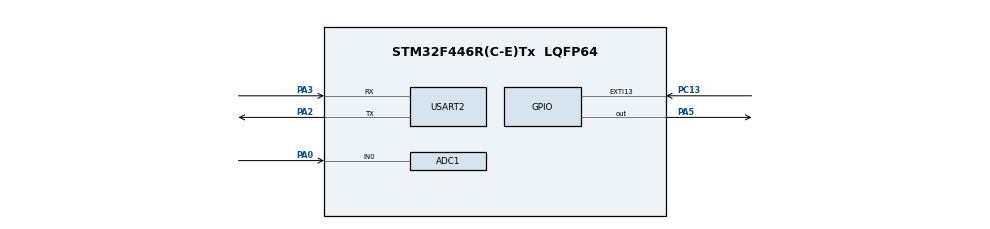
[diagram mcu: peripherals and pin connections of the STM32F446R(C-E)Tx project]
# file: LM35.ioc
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ADC1.Channel-0\#ChannelRegularConversion=ADC_CHANNEL_0
ADC1.Channel-1\#ChannelRegularConversion=ADC_CHANNEL_0
ADC1.Channel-10\#ChannelRegularConversion=ADC_CHANNEL_0
ADC1.Channel-11\#ChannelRegularConversion=ADC_CHANNEL_0
ADC1.Channel-12\#ChannelRegularConversion=ADC_CHANNEL_0
ADC1.Channel-13\#ChannelRegularConversion=ADC_CHANNEL_0
ADC1.Channel-14\#ChannelRegularConversion=ADC_CHANNEL_0
ADC1.Channel-15\#ChannelRegularConversion=ADC_CHANNEL_0
ADC1.Channel-2\#ChannelRegularConversion=ADC_CHANNEL_0
ADC1.Channel-3\#ChannelRegularConversion=ADC_CHANNEL_0
ADC1.Channel-4\#ChannelRegularConversion=ADC_CHANNEL_0
ADC1.Channel-5\#ChannelRegularConversion=ADC_CHANNEL_0
ADC1.Channel-6\#ChannelRegularConversion=ADC_CHANNEL_0
ADC1.Channel-7\#ChannelRegularConversion=ADC_CHANNEL_0
ADC1.Channel-8\#ChannelRegularConversion=ADC_CHANNEL_0
ADC1.Channel-9\#ChannelRegularConversion=ADC_CHANNEL_0
ADC1.ContinuousConvMode=ENABLE
ADC1.NbrOfConversion=16
ADC1.NbrOfConversionFlag=1
ADC1.Rank-0\#ChannelRegularConversion=1
ADC1.Rank-1\#ChannelRegularConversion=2
ADC1.Rank-10\#ChannelRegularConversion=11
ADC1.Rank-11\#ChannelRegularConversion=12
ADC1.Rank-12\#ChannelRegularConversion=13
ADC1.Rank-13\#ChannelRegularConversion=14
ADC1.Rank-14\#ChannelRegularConversion=15
ADC1.Rank-15\#ChannelRegularConversion=16
ADC1.Rank-2\#ChannelRegularConversion=3
ADC1.Rank-3\#ChannelRegularConversion=4
ADC1.Rank-4\#ChannelRegularConversion=5
ADC1.Rank-5\#ChannelRegularConversion=6
ADC1.Rank-6\#ChannelRegularConversion=7
ADC1.Rank-7\#ChannelRegularConversion=8
ADC1.Rank-8\#ChannelRegularConversion=9
ADC1.Rank-9\#ChannelRegularConversion=10
ADC1.SamplingTime-0\#ChannelRegularConversion=ADC_SAMPLETIME_3CYCLES
ADC1.SamplingTime-1\#ChannelRegularConversion=ADC_SAMPLETIME_3CYCLES
ADC1.SamplingTime-10\#ChannelRegularConversion=ADC_SAMPLETIME_3CYCLES
ADC1.SamplingTime-11\#ChannelRegularConversion=ADC_SAMPLETIME_3CYCLES
ADC1.SamplingTime-12\#ChannelRegularConversion=ADC_SAMPLETIME_3CYCLES
ADC1.SamplingTime-13\#ChannelRegularConversion=ADC_SAMPLETIME_3CYCLES
ADC1.SamplingTime-14\#ChannelRegularConversion=ADC_SAMPLETIME_3CYCLES
ADC1.SamplingTime-15\#ChannelRegularConversion=ADC_SAMPLETIME_3CYCLES
ADC1.SamplingTime-2\#ChannelRegularConversion=ADC_SAMPLETIME_3CYCLES
ADC1.SamplingTime-3\#ChannelRegularConversion=ADC_SAMPLETIME_3CYCLES
ADC1.SamplingTime-4\#ChannelRegularConversion=ADC_SAMPLETIME_3CYCLES
ADC1.SamplingTime-5\#ChannelRegularConversion=ADC_SAMPLETIME_3CYCLES
ADC1.SamplingTime-6\#ChannelRegularConversion=ADC_SAMPLETIME_3CYCLES
ADC1.SamplingTime-7\#ChannelRegularConversion=ADC_SAMPLETIME_3CYCLES
ADC1.SamplingTime-8\#ChannelRegularConversion=ADC_SAMPLETIME_3CYCLES
ADC1.SamplingTime-9\#ChannelRegularConversion=ADC_SAMPLETIME_3CYCLES
ADC1.ScanConvMode=ENABLE
ADC1.master=1
Dma.ADC1.0.Direction=DMA_PERIPH_TO_MEMORY
Dma.ADC1.0.FIFOMode=DMA_FIFOMODE_DISABLE
Dma.ADC1.0.Instance=DMA2_Stream0
Dma.ADC1.0.MemDataAlignment=DMA_MDATAALIGN_WORD
Dma.ADC1.0.MemInc=DMA_MINC_ENABLE
Dma.ADC1.0.Mode=DMA_CIRCULAR
Dma.ADC1.0.PeriphDataAlignment=DMA_PDATAALIGN_WORD
Dma.ADC1.0.PeriphInc=DMA_PINC_DISABLE
Dma.ADC1.0.Priority=DMA_PRIORITY_LOW
Dma.Request0=ADC1
Mcu.Family=STM32F4
Mcu.Name=STM32F446R(C-E)Tx
Mcu.Package=LQFP64
NVIC.DMA2_Stream0_IRQn=true\:0\:0\:false\:false\:true\:false\:true
NVIC.PriorityGroup=NVIC_PRIORITYGROUP_0
NVIC.RCC_IRQn=true\:0\:0\:false\:false\:true\:true\:false
PA0-WKUP.Signal=ADCx_IN0
PA13.Signal=SYS_JTMS-SWDIO
PA14.Signal=SYS_JTCK-SWCLK
PA2.GPIO_Mode=GPIO_MODE_AF_PP
PA2.GPIO_PuPd=GPIO_PULLUP
PA2.GPIO_Speed=GPIO_SPEED_FREQ_VERY_HIGH
PA2.Mode=Asynchronous
PA2.Signal=USART2_TX
PA3.GPIO_Mode=GPIO_MODE_AF_PP
PA3.GPIO_PuPd=GPIO_PULLUP
PA3.GPIO_Speed=GPIO_SPEED_FREQ_VERY_HIGH
PA3.Mode=Asynchronous
PA3.Signal=USART2_RX
PA5.GPIO_ModeDefaultOutputPP=GPIO_MODE_OUTPUT_PP
PA5.GPIO_PuPd=GPIO_NOPULL
PA5.GPIO_Speed=GPIO_SPEED_FREQ_LOW
PA5.PinState=GPIO_PIN_RESET
PA5.Signal=GPIO_Output
PB3.Signal=SYS_JTDO-SWO
PC13.GPIO_ModeDefaultEXTI=GPIO_MODE_IT_RISING
PC13.GPIO_PuPd=GPIO_NOPULL
PC13.Signal=GPXTI13
PC14-OSC32_IN.Signal=RCC_OSC32_IN
PC15-OSC32_OUT.Signal=RCC_OSC32_OUT
<<<<<<< HEAD
<<<<<<< HEAD
PH0-OSC_IN.Mode=HSE-External-Oscillator
PH0-OSC_IN.Signal=RCC_OSC_IN
PH1-OSC_OUT.Mode=HSE-External-Oscillator
=======
PH0-OSC_IN.Signal=RCC_OSC_IN
>>>>>>> parent of ff74db9... add RCC
=======
PH0-OSC_IN.Signal=RCC_OSC_IN
>>>>>>> parent of ff74db9... add RCC
PH1-OSC_OUT.Signal=RCC_OSC_OUT
ProjectManager.HeapSize=0x400
ProjectManager.StackSize=0x400
ProjectManager.TargetToolchain=TrueSTUDIO
<<<<<<< HEAD
RCC.APB1TimFreq_Value=36000000
RCC.PLLSourceVirtual=RCC_PLLSOURCE_HSE
RCC.SYSCLKSource=RCC_SYSCLKSOURCE_PLLCLK
=======
RCC.AHBFreq_Value=72000000
RCC.APB1CLKDivider=RCC_HCLK_DIV2
RCC.APB1Freq_Value=36000000
RCC.APB1TimFreq_Value=72000000
RCC.APB2Freq_Value=72000000
RCC.APB2TimFreq_Value=72000000
RCC.CortexFreq_Value=72000000
RCC.FLatency-AdvancedSettings=FLASH_LATENCY_2
RCC.HCLKFreq_Value=72000000
RCC.HSE_VALUE=8000000
RCC.HSI_VALUE=16000000
RCC.LSE_VALUE=32768
RCC.PLLM=8
RCC.PLLN=72
RCC.SYSCLKFreq_VALUE=72000000
RCC.SYSCLKSource=RCC_SYSCLKSOURCE_PLLCLK
RCC.USBFreq_Value=72000000
RCC.VCOOutputFreq_Value=144000000
>>>>>>> parent of ff74db9... add RCC
SH.ADCx_IN0.0=ADC1_IN0,IN0
USART2.VirtualMode=VM_ASYNC
board=NUCLEO-F446RE

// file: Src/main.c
/* USER CODE BEGIN Header */
/**
  ******************************************************************************
  * @file           : main.c
  * @brief          : Main program body
  ******************************************************************************
  * @attention
  *
  * <h2><center>&copy; Copyright (c) 2019 STMicroelectronics.
  * All rights reserved.</center></h2>
  *
  * This software component is licensed by ST under BSD 3-Clause license,
  * the "License"; You may not use this file except in compliance with the
  * License. You may obtain a copy of the License at:
  *                        opensource.org/licenses/BSD-3-Clause
  *
  ******************************************************************************
  */
/* USER CODE END Header */

#include "main.h"

ADC_HandleTypeDef hadc1;
DMA_HandleTypeDef hdma_adc1;

UART_HandleTypeDef huart2;

void SystemClock_Config(void);
static void MX_GPIO_Init(void);
static void MX_DMA_Init(void);
static void MX_ADC1_Init(void);
static void MX_USART2_UART_Init(void);
/* USER CODE BEGIN PFP */
void SET_ADCOption1 (FunctionalState NewState);
void SET_ADCOption2 (uint32_t ADCxDC2, FunctionalState NewState);
/* USER CODE END PFP */

/* USER CODE BEGIN 0 */
uint32_t adc_val, buffer;
void HAL_ADC_ConvCpltCallback(ADC_HandleTypeDef* hadc)
{

/* for INTERRUPT uncomment the line below */
//	buffer = HAL_ADC_GetValue(&hadc1);

/*If continuousconversion mode is DISABLED uncomment below*/
//HAL_ADC_Start_IT (&hadc1);

/* for DMA uncomment the line below */
	adc_val = buffer;
}

int __io_putchar(int ch)
 {
  uint8_t c[1];
  c[0] = ch & 0x00FF;
  HAL_UART_Transmit(&huart2, &*c, 1, 10);
  return ch;
 }

 int _write(int file,char *ptr, int len)
 {
  int DataIdx;
  for(DataIdx= 0; DataIdx< len; DataIdx++)
  {
  __io_putchar(*ptr++);
  }
 return len;
 }
/* USER CODE END 0 */

int main(void)
{

  /* MCU Configuration--------------------------------------------------------*/

  /* Reset of all peripherals, Initializes the Flash interface and the Systick. */
  HAL_Init();

  /* Configure the system clock */
  SystemClock_Config();

  /* Initialize all configured peripherals */
  MX_GPIO_Init();
  MX_DMA_Init();
  MX_ADC1_Init();
  MX_USART2_UART_Init();
  /* USER CODE BEGIN 2 */
  //SET_ADCOption1 (ENABLE);
 //SET_ADCOption2 (SYSCFG_PMC_ADCxDC2, ENABLE);
  /* USER CODE END 2 */

  /* Infinite loop */
  while (1)
  {

    /* USER CODE BEGIN 3 */
		HAL_ADC_Start (&hadc1);
	  HAL_ADC_PollForConversion(&hadc1, 10);  // poll for conversion
	  adc_val = HAL_ADC_GetValue(&hadc1);  // get the adc value
		printf("ADC_Value == %d \n\r", adc_val);
	//	HAL_ADC_Stop(&hadc1);  // stop adc
		HAL_Delay (50);  // wait for 500ms
  }
  /* USER CODE END 3 */
}

<<<<<<< HEAD
<<<<<<< HEAD
<<<<<<< HEAD
=======
=======
>>>>>>> parent of ff74db9... add RCC
=======
>>>>>>> parent of ff74db9... add RCC
/**
* @brief Enables or disables the ADC Option_1 configuration.
 * @param NewState: new state of the ADCDC1 bit.
 * This parameter can be: ENABLE or DISABLE.
 * @retval None
 */
void SET_ADCOption1 (FunctionalState NewState)
{

 /* ENABLE PWR clock */
	__HAL_RCC_PWR_CLK_ENABLE();

 if (NewState != DISABLE)
 {
 /* Set ADCDC1 bit */
 PWR->CR |= ((uint32_t)PWR_CR_ADCDC1);
 }
 else
 {
 /* Reset ADCDC1 bit */
 PWR->CR &= (uint32_t)(~PWR_CR_ADCDC1);
 }
}

/**
 * @brief Enables or disables the ADCx Option_2 configuration.
 * @param ADCxDC2: The ADCxDC2 bit to be used.
 * This parameter can be one of the following values:
 * @arg SYSCFG_PMC_ADCxDC2: All ADCxDC2 bits
 * @arg SYSCFG_PMC_ADC1DC2: ADC1DC2 bit
 * @arg SYSCFG_PMC_ADC2DC2: ADC2DC2 bit
 * @arg SYSCFG_PMC_ADC3DC2: ADC3DC2 bit
 * @param NewState: new state of the ADCxDC2 bit.
 * This parameter can be: ENABLE or DISABLE.
 * @retval None
 */
void SET_ADCOption2 (uint32_t ADCxDC2, FunctionalState NewState)
{

 /* Enable the SYSCFG clock*/
	__HAL_RCC_SYSCFG_CLK_ENABLE();

 if (NewState != DISABLE)
 {
 /* Set the ADCxDC2 */
 SYSCFG->PMC |= (uint32_t)ADCxDC2;
 }
 else
 {
 /* Reset the ADCxDC2 */
 SYSCFG->PMC &=(uint32_t)(~ADCxDC2);
}
}
>>>>>>> parent of ff74db9... add RCC

void SystemClock_Config(void)
{
  RCC_OscInitTypeDef RCC_OscInitStruct = {0};
  RCC_ClkInitTypeDef RCC_ClkInitStruct = {0};

  /** Configure the main internal regulator output voltage
  */
  __HAL_RCC_PWR_CLK_ENABLE();
  __HAL_PWR_VOLTAGESCALING_CONFIG(PWR_REGULATOR_VOLTAGE_SCALE3);
  /** Initializes the CPU, AHB and APB busses clocks
  */
<<<<<<< HEAD
<<<<<<< HEAD
<<<<<<< HEAD
  RCC_OscInitStruct.OscillatorType = RCC_OSCILLATORTYPE_HSE;
  RCC_OscInitStruct.HSEState = RCC_HSE_ON;
  RCC_OscInitStruct.PLL.PLLState = RCC_PLL_ON;
  RCC_OscInitStruct.PLL.PLLSource = RCC_PLLSOURCE_HSE;
  RCC_OscInitStruct.PLL.PLLM = 16;
  RCC_OscInitStruct.PLL.PLLN = 192;
=======
  RCC_OscInitStruct.OscillatorType = RCC_OSCILLATORTYPE_HSI;
  RCC_OscInitStruct.HSIState = RCC_HSI_ON;
  RCC_OscInitStruct.HSICalibrationValue = RCC_HSICALIBRATION_DEFAULT;
  RCC_OscInitStruct.PLL.PLLState = RCC_PLL_ON;
=======
  RCC_OscInitStruct.OscillatorType = RCC_OSCILLATORTYPE_HSI;
  RCC_OscInitStruct.HSIState = RCC_HSI_ON;
  RCC_OscInitStruct.HSICalibrationValue = RCC_HSICALIBRATION_DEFAULT;
  RCC_OscInitStruct.PLL.PLLState = RCC_PLL_ON;
>>>>>>> parent of ff74db9... add RCC
=======
  RCC_OscInitStruct.OscillatorType = RCC_OSCILLATORTYPE_HSI;
  RCC_OscInitStruct.HSIState = RCC_HSI_ON;
  RCC_OscInitStruct.HSICalibrationValue = RCC_HSICALIBRATION_DEFAULT;
  RCC_OscInitStruct.PLL.PLLState = RCC_PLL_ON;
>>>>>>> parent of ff74db9... add RCC
  RCC_OscInitStruct.PLL.PLLSource = RCC_PLLSOURCE_HSI;
  RCC_OscInitStruct.PLL.PLLM = 8;
  RCC_OscInitStruct.PLL.PLLN = 72;
>>>>>>> parent of ff74db9... add RCC
  RCC_OscInitStruct.PLL.PLLP = RCC_PLLP_DIV2;
  RCC_OscInitStruct.PLL.PLLQ = 2;
  RCC_OscInitStruct.PLL.PLLR = 2;
  if (HAL_RCC_OscConfig(&RCC_OscInitStruct) != HAL_OK)
  {
    Error_Handler();
  }
  /** Initializes the CPU, AHB and APB busses clocks
  */
  RCC_ClkInitStruct.ClockType = RCC_CLOCKTYPE_HCLK|RCC_CLOCKTYPE_SYSCLK
                              |RCC_CLOCKTYPE_PCLK1|RCC_CLOCKTYPE_PCLK2;
  RCC_ClkInitStruct.SYSCLKSource = RCC_SYSCLKSOURCE_PLLCLK;
  RCC_ClkInitStruct.AHBCLKDivider = RCC_SYSCLK_DIV1;
  RCC_ClkInitStruct.APB1CLKDivider = RCC_HCLK_DIV1;
  RCC_ClkInitStruct.APB2CLKDivider = RCC_HCLK_DIV1;

  if (HAL_RCC_ClockConfig(&RCC_ClkInitStruct, FLASH_LATENCY_0) != HAL_OK)
  {
    Error_Handler();
  }
}

static void MX_ADC1_Init(void)
{

  ADC_ChannelConfTypeDef sConfig = {0};

  /** Configure the global features of the ADC (Clock, Resolution, Data Alignment and number of conversion)
  */
  hadc1.Instance = ADC1;
  hadc1.Init.ClockPrescaler = ADC_CLOCK_SYNC_PCLK_DIV2;
  hadc1.Init.Resolution = ADC_RESOLUTION_12B;
  hadc1.Init.ScanConvMode = ENABLE;
  hadc1.Init.ContinuousConvMode = ENABLE;
  hadc1.Init.DiscontinuousConvMode = DISABLE;
  hadc1.Init.ExternalTrigConvEdge = ADC_EXTERNALTRIGCONVEDGE_NONE;
  hadc1.Init.ExternalTrigConv = ADC_SOFTWARE_START;
  hadc1.Init.DataAlign = ADC_DATAALIGN_RIGHT;
  hadc1.Init.NbrOfConversion = 16;
  hadc1.Init.DMAContinuousRequests = DISABLE;
  hadc1.Init.EOCSelection = ADC_EOC_SINGLE_CONV;
  if (HAL_ADC_Init(&hadc1) != HAL_OK)
  {
    Error_Handler();
  }
  /** Configure for the selected ADC regular channel its corresponding rank in the sequencer and its sample time.
  */
  sConfig.Channel = ADC_CHANNEL_0;
  sConfig.Rank = 1;
  sConfig.SamplingTime = ADC_SAMPLETIME_3CYCLES;
  if (HAL_ADC_ConfigChannel(&hadc1, &sConfig) != HAL_OK)
  {
    Error_Handler();
  }
  /** Configure for the selected ADC regular channel its corresponding rank in the sequencer and its sample time.
  */
  sConfig.Rank = 2;
  if (HAL_ADC_ConfigChannel(&hadc1, &sConfig) != HAL_OK)
  {
    Error_Handler();
  }
  /** Configure for the selected ADC regular channel its corresponding rank in the sequencer and its sample time.
  */
  sConfig.Rank = 3;
  if (HAL_ADC_ConfigChannel(&hadc1, &sConfig) != HAL_OK)
  {
    Error_Handler();
  }
  /** Configure for the selected ADC regular channel its corresponding rank in the sequencer and its sample time.
  */
  sConfig.Rank = 4;
  if (HAL_ADC_ConfigChannel(&hadc1, &sConfig) != HAL_OK)
  {
    Error_Handler();
  }
  /** Configure for the selected ADC regular channel its corresponding rank in the sequencer and its sample time.
  */
  sConfig.Rank = 5;
  if (HAL_ADC_ConfigChannel(&hadc1, &sConfig) != HAL_OK)
  {
    Error_Handler();
  }
  /** Configure for the selected ADC regular channel its corresponding rank in the sequencer and its sample time.
  */
  sConfig.Rank = 6;
  if (HAL_ADC_ConfigChannel(&hadc1, &sConfig) != HAL_OK)
  {
    Error_Handler();
  }
  /** Configure for the selected ADC regular channel its corresponding rank in the sequencer and its sample time.
  */
  sConfig.Rank = 7;
  if (HAL_ADC_ConfigChannel(&hadc1, &sConfig) != HAL_OK)
  {
    Error_Handler();
  }
  /** Configure for the selected ADC regular channel its corresponding rank in the sequencer and its sample time.
  */
  sConfig.Rank = 8;
  if (HAL_ADC_ConfigChannel(&hadc1, &sConfig) != HAL_OK)
  {
    Error_Handler();
  }
  /** Configure for the selected ADC regular channel its corresponding rank in the sequencer and its sample time.
  */
  sConfig.Rank = 9;
  if (HAL_ADC_ConfigChannel(&hadc1, &sConfig) != HAL_OK)
  {
    Error_Handler();
  }
  /** Configure for the selected ADC regular channel its corresponding rank in the sequencer and its sample time.
  */
  sConfig.Rank = 10;
  if (HAL_ADC_ConfigChannel(&hadc1, &sConfig) != HAL_OK)
  {
    Error_Handler();
  }
  /** Configure for the selected ADC regular channel its corresponding rank in the sequencer and its sample time.
  */
  sConfig.Rank = 11;
  if (HAL_ADC_ConfigChannel(&hadc1, &sConfig) != HAL_OK)
  {
    Error_Handler();
  }
  /** Configure for the selected ADC regular channel its corresponding rank in the sequencer and its sample time.
  */
  sConfig.Rank = 12;
  if (HAL_ADC_ConfigChannel(&hadc1, &sConfig) != HAL_OK)
  {
    Error_Handler();
  }
  /** Configure for the selected ADC regular channel its corresponding rank in the sequencer and its sample time.
  */
  sConfig.Rank = 13;
  if (HAL_ADC_ConfigChannel(&hadc1, &sConfig) != HAL_OK)
  {
    Error_Handler();
  }
  /** Configure for the selected ADC regular channel its corresponding rank in the sequencer and its sample time.
  */
  sConfig.Rank = 14;
  if (HAL_ADC_ConfigChannel(&hadc1, &sConfig) != HAL_OK)
  {
    Error_Handler();
  }
  /** Configure for the selected ADC regular channel its corresponding rank in the sequencer and its sample time.
  */
  sConfig.Rank = 15;
  if (HAL_ADC_ConfigChannel(&hadc1, &sConfig) != HAL_OK)
  {
    Error_Handler();
  }
  /** Configure for the selected ADC regular channel its corresponding rank in the sequencer and its sample time.
  */
  sConfig.Rank = 16;
  if (HAL_ADC_ConfigChannel(&hadc1, &sConfig) != HAL_OK)
  {
    Error_Handler();
  }

}

static void MX_USART2_UART_Init(void)
{

  huart2.Instance = USART2;
  huart2.Init.BaudRate = 115200;
  huart2.Init.WordLength = UART_WORDLENGTH_8B;
  huart2.Init.StopBits = UART_STOPBITS_1;
  huart2.Init.Parity = UART_PARITY_NONE;
  huart2.Init.Mode = UART_MODE_TX_RX;
  huart2.Init.HwFlowCtl = UART_HWCONTROL_NONE;
  huart2.Init.OverSampling = UART_OVERSAMPLING_16;
  if (HAL_UART_Init(&huart2) != HAL_OK)
  {
    Error_Handler();
  }

}

static void MX_DMA_Init(void)
{

  /* DMA controller clock enable */
  __HAL_RCC_DMA2_CLK_ENABLE();

  /* DMA interrupt init */
  /* DMA2_Stream0_IRQn interrupt configuration */
  HAL_NVIC_SetPriority(DMA2_Stream0_IRQn, 0, 0);
  HAL_NVIC_EnableIRQ(DMA2_Stream0_IRQn);

}

static void MX_GPIO_Init(void)
{
  GPIO_InitTypeDef GPIO_InitStruct = {0};

  /* GPIO Ports Clock Enable */
  __HAL_RCC_GPIOC_CLK_ENABLE();
  __HAL_RCC_GPIOH_CLK_ENABLE();
  __HAL_RCC_GPIOA_CLK_ENABLE();
  __HAL_RCC_GPIOB_CLK_ENABLE();

  /*Configure GPIO pin Output Level */
  HAL_GPIO_WritePin(GPIOA, GPIO_PIN_5, GPIO_PIN_RESET);

  /*Configure GPIO pin : PC13 */
  GPIO_InitStruct.Pin = GPIO_PIN_13;
  GPIO_InitStruct.Mode = GPIO_MODE_IT_RISING;
  GPIO_InitStruct.Pull = GPIO_NOPULL;
  HAL_GPIO_Init(GPIOC, &GPIO_InitStruct);

  /*Configure GPIO pin : PA5 */
  GPIO_InitStruct.Pin = GPIO_PIN_5;
  GPIO_InitStruct.Mode = GPIO_MODE_OUTPUT_PP;
  GPIO_InitStruct.Pull = GPIO_NOPULL;
  GPIO_InitStruct.Speed = GPIO_SPEED_FREQ_LOW;
  HAL_GPIO_Init(GPIOA, &GPIO_InitStruct);

}

/* USER CODE BEGIN 4 */
/**
* @brief Enables or disables the ADC Option_1 configuration.
 * @param NewState: new state of the ADCDC1 bit.
 * This parameter can be: ENABLE or DISABLE.
 * @retval None
 */
void SET_ADCOption1 (FunctionalState NewState)
{

 /* ENABLE PWR clock */
	__HAL_RCC_PWR_CLK_ENABLE();

 if (NewState != DISABLE)
 {
 /* Set ADCDC1 bit */
 PWR->CR |= ((uint32_t)PWR_CR_ADCDC1);
 }
 else
 {
 /* Reset ADCDC1 bit */
 PWR->CR &= (uint32_t)(~PWR_CR_ADCDC1);
 }
}

/**
 * @brief Enables or disables the ADCx Option_2 configuration.
 * @param ADCxDC2: The ADCxDC2 bit to be used.
 * This parameter can be one of the following values:
 * @arg SYSCFG_PMC_ADCxDC2: All ADCxDC2 bits
 * @arg SYSCFG_PMC_ADC1DC2: ADC1DC2 bit
 * @arg SYSCFG_PMC_ADC2DC2: ADC2DC2 bit
 * @arg SYSCFG_PMC_ADC3DC2: ADC3DC2 bit
 * @param NewState: new state of the ADCxDC2 bit.
 * This parameter can be: ENABLE or DISABLE.
 * @retval None
 */
void SET_ADCOption2 (uint32_t ADCxDC2, FunctionalState NewState)
{

 /* Enable the SYSCFG clock*/
	__HAL_RCC_SYSCFG_CLK_ENABLE();

 if (NewState != DISABLE)
 {
 /* Set the ADCxDC2 */
 SYSCFG->PMC |= (uint32_t)ADCxDC2;
 }
 else
 {
 /* Reset the ADCxDC2 */
 SYSCFG->PMC &=(uint32_t)(~ADCxDC2);
}
}
/* USER CODE END 4 */

void Error_Handler(void)
{
}

/************************ (C) COPYRIGHT STMicroelectronics *****END OF FILE****/
